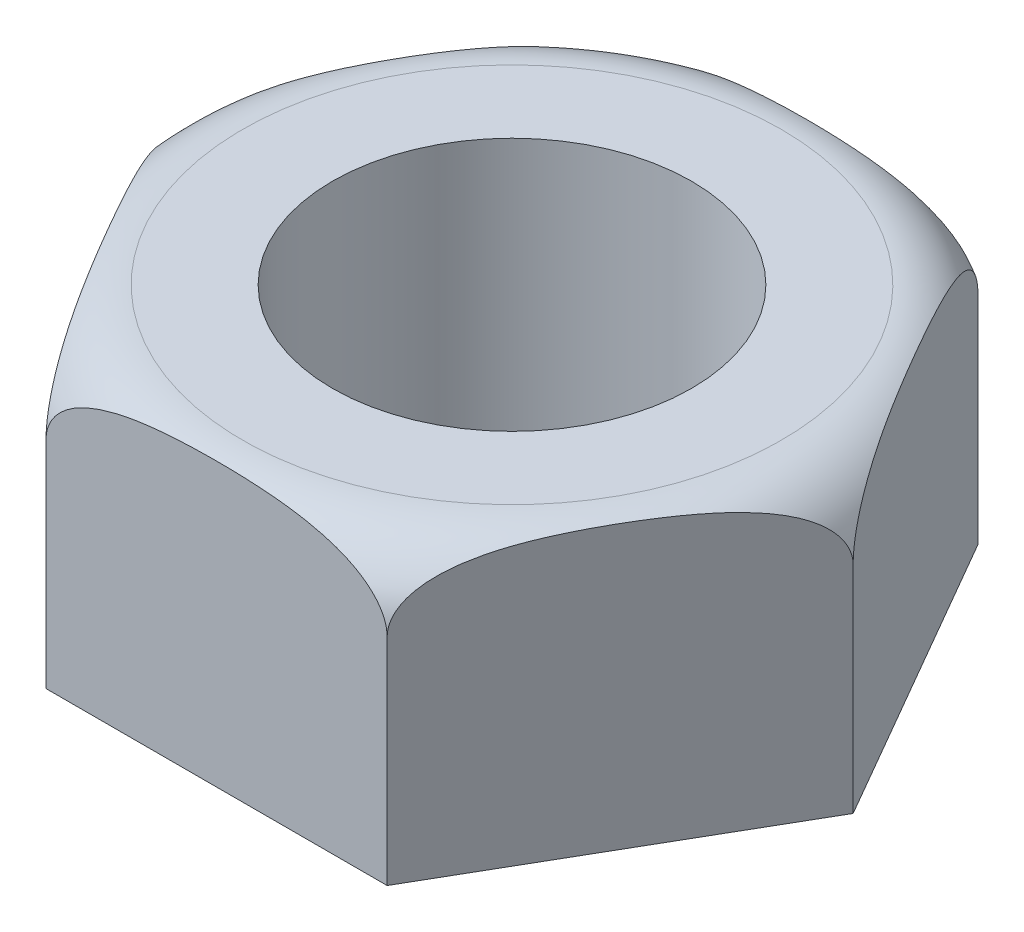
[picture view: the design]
ISO-10303-21;
HEADER;
FILE_DESCRIPTION(('STEP AP214'),'2;1');
FILE_NAME('part.step','',(''),(''),'','','');
FILE_SCHEMA(('AUTOMOTIVE_DESIGN { 1 0 10303 214 1 1 1 1 }'));
ENDSEC;
DATA;
#1=APPLICATION_CONTEXT('core data for automotive mechanical design processes');
#2=APPLICATION_PROTOCOL_DEFINITION('international standard','automotive_design',2000,#1);
#3=PRODUCT_CONTEXT('',#1,'mechanical');
#4=PRODUCT('Part','Part','',(#3));
#5=PRODUCT_RELATED_PRODUCT_CATEGORY('part','',(#4));
#6=PRODUCT_DEFINITION_FORMATION('','',#4);
#7=PRODUCT_DEFINITION_CONTEXT('part definition',#1,'design');
#8=PRODUCT_DEFINITION('design','',#6,#7);
#9=PRODUCT_DEFINITION_SHAPE('','',#8);
#10=(LENGTH_UNIT() NAMED_UNIT(*) SI_UNIT(.MILLI.,.METRE.));
#11=(NAMED_UNIT(*) PLANE_ANGLE_UNIT() SI_UNIT($,.RADIAN.));
#12=(NAMED_UNIT(*) SI_UNIT($,.STERADIAN.) SOLID_ANGLE_UNIT());
#13=UNCERTAINTY_MEASURE_WITH_UNIT(LENGTH_MEASURE(1.E-05),#10,'distance_accuracy_value','');
#14=(GEOMETRIC_REPRESENTATION_CONTEXT(3) GLOBAL_UNCERTAINTY_ASSIGNED_CONTEXT((#13)) GLOBAL_UNIT_ASSIGNED_CONTEXT((#10,
#11,#12)) REPRESENTATION_CONTEXT('',''));
#15=CARTESIAN_POINT('',(0.,0.,0.));
#16=DIRECTION('',(0.,0.,1.));
#17=DIRECTION('',(1.,0.,0.));
#18=AXIS2_PLACEMENT_3D('',#15,#16,#17);
#19=CARTESIAN_POINT('',(4.75,8.00000000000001,8.22724133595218));
#20=DIRECTION('',(0.,-1.,0.));
#21=DIRECTION('',(0.,0.,-1.));
#22=AXIS2_PLACEMENT_3D('',#19,#20,#21);
#23=PLANE('',#22);
#24=CARTESIAN_POINT('',(0.,8.00000000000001,0.));
#25=DIRECTION('',(0.,-1.,0.));
#26=DIRECTION('',(0.,0.,-1.));
#27=AXIS2_PLACEMENT_3D('',#24,#25,#26);
#28=CIRCLE('',#27,7.49999999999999);
#29=CARTESIAN_POINT('',(0.,8.00000000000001,-7.50000000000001));
#30=VERTEX_POINT('',#29);
#31=EDGE_CURVE('E214',#30,#30,#28,.T.);
#32=ORIENTED_EDGE('',*,*,#31,.F.);
#33=EDGE_LOOP('',(#32));
#34=FACE_BOUND('',#33,.T.);
#35=CARTESIAN_POINT('',(0.,8.00000000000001,0.));
#36=DIRECTION('',(0.,1.,0.));
#37=DIRECTION('',(0.,0.,1.));
#38=AXIS2_PLACEMENT_3D('',#35,#36,#37);
#39=CIRCLE('',#38,5.);
#40=CARTESIAN_POINT('',(0.,8.00000000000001,5.00000000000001));
#41=VERTEX_POINT('',#40);
#42=EDGE_CURVE('E134',#41,#41,#39,.T.);
#43=ORIENTED_EDGE('',*,*,#42,.F.);
#44=EDGE_LOOP('',(#43));
#45=FACE_BOUND('',#44,.T.);
#46=ADVANCED_FACE('F32',(#34,#45),#23,.F.);
#47=CARTESIAN_POINT('',(4.75,0.,8.22724133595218));
#48=DIRECTION('',(0.,-1.,0.));
#49=DIRECTION('',(0.,0.,-1.));
#50=AXIS2_PLACEMENT_3D('',#47,#48,#49);
#51=PLANE('',#50);
#52=DIRECTION('',(0.5,0.,-0.866025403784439));
#53=VECTOR('',#52,1.);
#54=CARTESIAN_POINT('',(4.75,0.,8.22724133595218));
#55=LINE('',#54,#53);
#56=CARTESIAN_POINT('',(4.75,0.,8.22724133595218));
#57=VERTEX_POINT('',#56);
#58=CARTESIAN_POINT('',(9.5,0.,0.));
#59=VERTEX_POINT('',#58);
#60=EDGE_CURVE('E132',#57,#59,#55,.T.);
#61=ORIENTED_EDGE('',*,*,#60,.F.);
#62=DIRECTION('',(1.,0.,0.));
#63=VECTOR('',#62,1.);
#64=CARTESIAN_POINT('',(-4.75000000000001,0.,8.22724133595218));
#65=LINE('',#64,#63);
#66=CARTESIAN_POINT('',(-4.75000000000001,0.,8.22724133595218));
#67=VERTEX_POINT('',#66);
#68=EDGE_CURVE('E121',#67,#57,#65,.T.);
#69=ORIENTED_EDGE('',*,*,#68,.F.);
#70=DIRECTION('',(0.500000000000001,0.,0.86602540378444));
#71=VECTOR('',#70,1.);
#72=CARTESIAN_POINT('',(-9.50000000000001,0.,0.));
#73=LINE('',#72,#71);
#74=CARTESIAN_POINT('',(-9.50000000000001,0.,0.));
#75=VERTEX_POINT('',#74);
#76=EDGE_CURVE('E123',#75,#67,#73,.T.);
#77=ORIENTED_EDGE('',*,*,#76,.F.);
#78=DIRECTION('',(-0.500000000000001,0.,0.86602540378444));
#79=VECTOR('',#78,1.);
#80=CARTESIAN_POINT('',(-4.75000000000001,0.,-8.22724133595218));
#81=LINE('',#80,#79);
#82=CARTESIAN_POINT('',(-4.75000000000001,0.,-8.22724133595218));
#83=VERTEX_POINT('',#82);
#84=EDGE_CURVE('E126',#83,#75,#81,.T.);
#85=ORIENTED_EDGE('',*,*,#84,.F.);
#86=DIRECTION('',(-1.,0.,0.));
#87=VECTOR('',#86,1.);
#88=CARTESIAN_POINT('',(4.74999999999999,0.,-8.22724133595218));
#89=LINE('',#88,#87);
#90=CARTESIAN_POINT('',(4.74999999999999,0.,-8.22724133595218));
#91=VERTEX_POINT('',#90);
#92=EDGE_CURVE('E129',#91,#83,#89,.T.);
#93=ORIENTED_EDGE('',*,*,#92,.F.);
#94=DIRECTION('',(-0.500000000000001,0.,-0.86602540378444));
#95=VECTOR('',#94,1.);
#96=CARTESIAN_POINT('',(9.5,0.,0.));
#97=LINE('',#96,#95);
#98=EDGE_CURVE('E111',#59,#91,#97,.T.);
#99=ORIENTED_EDGE('',*,*,#98,.F.);
#100=EDGE_LOOP('',(#61,#69,#77,#85,#93,#99));
#101=FACE_BOUND('',#100,.T.);
#102=CARTESIAN_POINT('',(0.,0.,0.));
#103=DIRECTION('',(0.,1.,0.));
#104=DIRECTION('',(0.,0.,1.));
#105=AXIS2_PLACEMENT_3D('',#102,#103,#104);
#106=CIRCLE('',#105,5.);
#107=CARTESIAN_POINT('',(0.,0.,5.00000000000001));
#108=VERTEX_POINT('',#107);
#109=EDGE_CURVE('E137',#108,#108,#106,.T.);
#110=ORIENTED_EDGE('',*,*,#109,.T.);
#111=EDGE_LOOP('',(#110));
#112=FACE_BOUND('',#111,.T.);
#113=ADVANCED_FACE('F185',(#101,#112),#51,.T.);
#114=CARTESIAN_POINT('',(4.75,8.00000000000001,8.22724133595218));
#115=DIRECTION('',(-0.866025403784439,0.,-0.5));
#116=DIRECTION('',(-0.5,0.,0.866025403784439));
#117=AXIS2_PLACEMENT_3D('',#114,#115,#116);
#118=PLANE('',#117);
#119=DIRECTION('',(0.,-1.,0.));
#120=VECTOR('',#119,1.);
#121=CARTESIAN_POINT('',(9.5,8.00000000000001,0.));
#122=LINE('',#121,#120);
#123=CARTESIAN_POINT('',(9.5,6.00000000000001,0.));
#124=VERTEX_POINT('',#123);
#125=EDGE_CURVE('E46',#124,#59,#122,.T.);
#126=ORIENTED_EDGE('',*,*,#125,.F.);
#127=CARTESIAN_POINT('',(9.49999999,5.9998,1.73205078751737E-08));
#128=CARTESIAN_POINT('',(9.50000570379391,6.02953854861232,-9.87926084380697E-06));
#129=CARTESIAN_POINT('',(9.49934209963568,6.05926118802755,0.00113951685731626));
#130=CARTESIAN_POINT('',(9.49670692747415,6.11845298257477,0.00570376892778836));
#131=CARTESIAN_POINT('',(9.4947362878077,6.14792230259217,0.009117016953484));
#132=CARTESIAN_POINT('',(9.48695380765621,6.23517168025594,0.0225966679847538));
#133=CARTESIAN_POINT('',(9.47927026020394,6.29231817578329,0.0359049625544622));
#134=CARTESIAN_POINT('',(9.45949602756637,6.40322520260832,0.0701549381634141));
#135=CARTESIAN_POINT('',(9.44741651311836,6.45699391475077,0.0910772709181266));
#136=CARTESIAN_POINT('',(9.41956311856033,6.56064404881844,0.139320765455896));
#137=CARTESIAN_POINT('',(9.40378132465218,6.61051683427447,0.166655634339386));
#138=CARTESIAN_POINT('',(9.35888397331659,6.73463561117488,0.244420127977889));
#139=CARTESIAN_POINT('',(9.32745343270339,6.80552710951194,0.298859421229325));
#140=CARTESIAN_POINT('',(9.25945945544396,6.93663016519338,0.416628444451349));
#141=CARTESIAN_POINT('',(9.22288378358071,6.99681546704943,0.479979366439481));
#142=CARTESIAN_POINT('',(9.15250995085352,7.09866418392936,0.601870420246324));
#143=CARTESIAN_POINT('',(9.11921583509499,7.14174925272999,0.659537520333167));
#144=CARTESIAN_POINT('',(9.05087560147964,7.22201196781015,0.777906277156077));
#145=CARTESIAN_POINT('',(9.0158281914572,7.25918517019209,0.83861017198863));
#146=CARTESIAN_POINT('',(8.94441863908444,7.32840115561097,0.962295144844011));
#147=CARTESIAN_POINT('',(8.90805407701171,7.36043384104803,1.02528041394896));
#148=CARTESIAN_POINT('',(8.83442786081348,7.41994367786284,1.15280476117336));
#149=CARTESIAN_POINT('',(8.79716649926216,7.44742229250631,1.21734333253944));
#150=CARTESIAN_POINT('',(8.70691244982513,7.50865232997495,1.37366793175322));
#151=CARTESIAN_POINT('',(8.65359886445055,7.54050535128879,1.46600977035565));
#152=CARTESIAN_POINT('',(8.54611149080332,7.59783939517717,1.65218336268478));
#153=CARTESIAN_POINT('',(8.49193727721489,7.62331715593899,1.74601585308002));
#154=CARTESIAN_POINT('',(8.38294500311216,7.6690358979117,1.93479600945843));
#155=CARTESIAN_POINT('',(8.32812595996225,7.68926737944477,2.02974537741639));
#156=CARTESIAN_POINT('',(8.21812420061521,7.72535220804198,2.22027401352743));
#157=CARTESIAN_POINT('',(8.1629414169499,7.74120471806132,2.31585339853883));
#158=CARTESIAN_POINT('',(8.05212864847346,7.76932967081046,2.50778674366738));
#159=CARTESIAN_POINT('',(7.99649775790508,7.78158760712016,2.60414227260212));
#160=CARTESIAN_POINT('',(7.88508651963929,7.80304965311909,2.79711219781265));
#161=CARTESIAN_POINT('',(7.82930615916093,7.81225349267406,2.89372661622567));
#162=CARTESIAN_POINT('',(7.71771510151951,7.82807918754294,3.08700799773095));
#163=CARTESIAN_POINT('',(7.66190449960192,7.83470377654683,3.18367479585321));
#164=CARTESIAN_POINT('',(7.55022830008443,7.84574609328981,3.3771036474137));
#165=CARTESIAN_POINT('',(7.49436270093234,7.85016375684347,3.4738657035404));
#166=CARTESIAN_POINT('',(7.36497862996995,7.85813362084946,3.69796548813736));
#167=CARTESIAN_POINT('',(7.29144917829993,7.86097352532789,3.82532223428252));
#168=CARTESIAN_POINT('',(7.14437827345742,7.86357402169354,4.08005651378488));
#169=CARTESIAN_POINT('',(7.07083682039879,7.86333464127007,4.20743404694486));
#170=CARTESIAN_POINT('',(6.92391404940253,7.85975368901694,4.4619117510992));
#171=CARTESIAN_POINT('',(6.85053269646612,7.85641810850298,4.5890119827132));
#172=CARTESIAN_POINT('',(6.70383188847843,7.84631582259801,4.84310523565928));
#173=CARTESIAN_POINT('',(6.63051242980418,7.8395493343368,4.97009826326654));
#174=CARTESIAN_POINT('',(6.48229282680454,7.82172370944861,5.2268221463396));
#175=CARTESIAN_POINT('',(6.40739547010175,7.81056863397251,5.35654817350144));
#176=CARTESIAN_POINT('',(6.25782508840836,7.78290463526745,5.61561167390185));
#177=CARTESIAN_POINT('',(6.18315211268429,7.76639461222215,5.74494906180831));
#178=CARTESIAN_POINT('',(6.03429411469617,7.72654851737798,6.00277867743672));
#179=CARTESIAN_POINT('',(5.96010883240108,7.70321644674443,6.13127135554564));
#180=CARTESIAN_POINT('',(5.81258009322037,7.64776448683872,6.38679862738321));
#181=CARTESIAN_POINT('',(5.73923620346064,7.61564934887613,6.51383397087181));
#182=CARTESIAN_POINT('',(5.59146025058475,7.53873440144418,6.76978942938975));
#183=CARTESIAN_POINT('',(5.51707923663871,7.49353181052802,6.89862112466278));
#184=CARTESIAN_POINT('',(5.37111873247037,7.38716305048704,7.15143213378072));
#185=CARTESIAN_POINT('',(5.29953820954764,7.32600283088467,7.27541323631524));
#186=CARTESIAN_POINT('',(5.17937365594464,7.20116047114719,7.48354434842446));
#187=CARTESIAN_POINT('',(5.1295960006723,7.14213802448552,7.56976177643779));
#188=CARTESIAN_POINT('',(5.03486652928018,7.01010975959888,7.7338380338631));
#189=CARTESIAN_POINT('',(4.98990435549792,6.9371349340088,7.81171480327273));
#190=CARTESIAN_POINT('',(4.92242614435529,6.8038929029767,7.92859049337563));
#191=CARTESIAN_POINT('',(4.897608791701,6.74831405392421,7.9715754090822));
#192=CARTESIAN_POINT('',(4.8524501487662,6.63023767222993,8.04979247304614));
#193=CARTESIAN_POINT('',(4.83210382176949,6.5677480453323,8.08503334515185));
#194=CARTESIAN_POINT('',(4.80038822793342,6.44799425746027,8.13996636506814));
#195=CARTESIAN_POINT('',(4.78806973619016,6.39174158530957,8.16130261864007));
#196=CARTESIAN_POINT('',(4.76830108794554,6.27594427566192,8.19554292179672));
#197=CARTESIAN_POINT('',(4.76084014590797,6.21640725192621,8.20846565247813));
#198=CARTESIAN_POINT('',(4.75407698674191,6.13023460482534,8.22017978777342));
#199=CARTESIAN_POINT('',(4.75254893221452,6.10424504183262,8.22282645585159));
#200=CARTESIAN_POINT('',(4.75050876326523,6.05210815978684,8.22636013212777));
#201=CARTESIAN_POINT('',(4.74999661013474,6.02596084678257,8.22724720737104));
#202=CARTESIAN_POINT('',(4.75000001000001,5.9998,8.22724131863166));
#203=B_SPLINE_CURVE_WITH_KNOTS('',3,(#127,#128,#129,#130,#131,#132,#133,#134,#135,#136,#137,
#138,#139,#140,#141,#142,#143,#144,#145,#146,#147,#148,#149,#150,#151,#152,#153,#154,#155,#156,
#157,#158,#159,#160,#161,#162,#163,#164,#165,#166,#167,#168,#169,#170,#171,#172,#173,#174,#175,
#176,#177,#178,#179,#180,#181,#182,#183,#184,#185,#186,#187,#188,#189,#190,#191,#192,#193,#194,
#195,#196,#197,#198,#199,#200,#201,#202),.UNSPECIFIED.,.F.,.F.,(4,2,2,2,2,2,2,2,2,2,2,2,2,2,2,2,
2,2,2,2,2,2,2,2,2,2,2,2,2,2,2,2,2,2,2,2,2,4),(0.,0.0891552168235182,0.178247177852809,
0.354877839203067,0.531062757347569,0.707627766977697,0.990252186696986,1.27356042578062,
1.51115713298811,1.74893160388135,1.9871675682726,2.22532683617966,2.55891555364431,
2.89267459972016,3.22703384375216,3.56145695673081,3.89721167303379,4.23299607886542,
4.56842361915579,4.90386091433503,5.34508340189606,5.78630192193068,6.22666843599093,
6.66700708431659,7.11756063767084,7.56820678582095,8.01858915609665,8.46872836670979,
8.93454308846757,9.40018438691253,9.74654054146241,10.0921360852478,10.3150195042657,
10.5376505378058,10.7211584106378,10.9042574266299,10.9826961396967,11.0611318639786),.UNSPECIFIED.);
#204=CARTESIAN_POINT('',(4.74999999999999,6.00000000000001,8.22724133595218));
#205=VERTEX_POINT('',#204);
#206=EDGE_CURVE('E95',#124,#205,#203,.T.);
#207=ORIENTED_EDGE('',*,*,#206,.T.);
#208=DIRECTION('',(0.,-1.,0.));
#209=VECTOR('',#208,1.);
#210=CARTESIAN_POINT('',(4.75,8.00000000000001,8.22724133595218));
#211=LINE('',#210,#209);
#212=EDGE_CURVE('E60',#205,#57,#211,.T.);
#213=ORIENTED_EDGE('',*,*,#212,.T.);
#214=ORIENTED_EDGE('',*,*,#60,.T.);
#215=EDGE_LOOP('',(#126,#207,#213,#214));
#216=FACE_BOUND('',#215,.T.);
#217=ADVANCED_FACE('F34',(#216),#118,.F.);
#218=CARTESIAN_POINT('',(9.5,8.00000000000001,0.));
#219=DIRECTION('',(-0.86602540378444,0.,0.500000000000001));
#220=DIRECTION('',(0.500000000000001,0.,0.86602540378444));
#221=AXIS2_PLACEMENT_3D('',#218,#219,#220);
#222=PLANE('',#221);
#223=DIRECTION('',(0.,-1.,0.));
#224=VECTOR('',#223,1.);
#225=CARTESIAN_POINT('',(4.74999999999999,8.00000000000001,-8.22724133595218));
#226=LINE('',#225,#224);
#227=CARTESIAN_POINT('',(4.74999999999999,6.00000000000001,-8.22724133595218));
#228=VERTEX_POINT('',#227);
#229=EDGE_CURVE('E104',#228,#91,#226,.T.);
#230=ORIENTED_EDGE('',*,*,#229,.F.);
#231=CARTESIAN_POINT('',(4.75000001,5.9998,-8.22724131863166));
#232=CARTESIAN_POINT('',(4.74999429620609,6.02953854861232,-8.22725121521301));
#233=CARTESIAN_POINT('',(4.75065790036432,6.05926118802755,-8.22610181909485));
#234=CARTESIAN_POINT('',(4.75329307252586,6.11845298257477,-8.22153756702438));
#235=CARTESIAN_POINT('',(4.7552637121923,6.14792230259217,-8.21812431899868));
#236=CARTESIAN_POINT('',(4.76304619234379,6.23517168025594,-8.20464466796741));
#237=CARTESIAN_POINT('',(4.77072973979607,6.29231817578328,-8.1913363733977));
#238=CARTESIAN_POINT('',(4.79050397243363,6.40322520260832,-8.15708639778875));
#239=CARTESIAN_POINT('',(4.80258348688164,6.45699391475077,-8.13616406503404));
#240=CARTESIAN_POINT('',(4.83043688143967,6.56064404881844,-8.08792057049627));
#241=CARTESIAN_POINT('',(4.84621867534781,6.61051683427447,-8.06058570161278));
#242=CARTESIAN_POINT('',(4.8911160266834,6.73463561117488,-7.98282120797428));
#243=CARTESIAN_POINT('',(4.92254656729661,6.80552710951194,-7.92838191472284));
#244=CARTESIAN_POINT('',(4.99054054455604,6.93663016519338,-7.81061289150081));
#245=CARTESIAN_POINT('',(5.0271162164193,6.99681546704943,-7.74726196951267));
#246=CARTESIAN_POINT('',(5.09749004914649,7.09866418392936,-7.62537091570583));
#247=CARTESIAN_POINT('',(5.13078416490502,7.14174925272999,-7.56770381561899));
#248=CARTESIAN_POINT('',(5.19912439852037,7.22201196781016,-7.44933505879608));
#249=CARTESIAN_POINT('',(5.2341718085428,7.2591851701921,-7.38863116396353));
#250=CARTESIAN_POINT('',(5.30558136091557,7.32840115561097,-7.26494619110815));
#251=CARTESIAN_POINT('',(5.34194592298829,7.36043384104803,-7.2019609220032));
#252=CARTESIAN_POINT('',(5.41557213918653,7.41994367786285,-7.0744365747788));
#253=CARTESIAN_POINT('',(5.45283350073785,7.44742229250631,-7.00989800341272));
#254=CARTESIAN_POINT('',(5.54308755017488,7.50865232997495,-6.85357340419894));
#255=CARTESIAN_POINT('',(5.59640113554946,7.5405053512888,-6.76123156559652));
#256=CARTESIAN_POINT('',(5.70388850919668,7.59783939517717,-6.57505797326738));
#257=CARTESIAN_POINT('',(5.75806272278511,7.62331715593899,-6.48122548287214));
#258=CARTESIAN_POINT('',(5.86705499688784,7.6690358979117,-6.29244532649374));
#259=CARTESIAN_POINT('',(5.92187404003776,7.68926737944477,-6.19749595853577));
#260=CARTESIAN_POINT('',(6.03187579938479,7.72535220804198,-6.00696732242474));
#261=CARTESIAN_POINT('',(6.0870585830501,7.74120471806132,-5.91138793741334));
#262=CARTESIAN_POINT('',(6.19787135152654,7.76932967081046,-5.71945459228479));
#263=CARTESIAN_POINT('',(6.25350224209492,7.78158760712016,-5.62309906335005));
#264=CARTESIAN_POINT('',(6.36491348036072,7.80304965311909,-5.43012913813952));
#265=CARTESIAN_POINT('',(6.42069384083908,7.81225349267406,-5.3335147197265));
#266=CARTESIAN_POINT('',(6.53228489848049,7.82807918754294,-5.14023333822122));
#267=CARTESIAN_POINT('',(6.58809550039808,7.83470377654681,-5.04356654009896));
#268=CARTESIAN_POINT('',(6.69977169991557,7.84574609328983,-4.85013768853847));
#269=CARTESIAN_POINT('',(6.75563729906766,7.85016375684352,-4.75337563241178));
#270=CARTESIAN_POINT('',(6.88502137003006,7.85813362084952,-4.52927584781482));
#271=CARTESIAN_POINT('',(6.95855082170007,7.86097352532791,-4.40191910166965));
#272=CARTESIAN_POINT('',(7.10562172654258,7.86357402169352,-4.14718482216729));
#273=CARTESIAN_POINT('',(7.17916317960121,7.86333464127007,-4.01980728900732));
#274=CARTESIAN_POINT('',(7.32608595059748,7.85975368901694,-3.76532958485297));
#275=CARTESIAN_POINT('',(7.39946730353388,7.85641810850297,-3.63822935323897));
#276=CARTESIAN_POINT('',(7.54616811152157,7.84631582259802,-3.38413610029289));
#277=CARTESIAN_POINT('',(7.61948757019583,7.83954933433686,-3.25714307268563));
#278=CARTESIAN_POINT('',(7.76770717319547,7.82172370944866,-3.00041918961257));
#279=CARTESIAN_POINT('',(7.84260452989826,7.81056863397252,-2.87069316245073));
#280=CARTESIAN_POINT('',(7.99217491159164,7.78290463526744,-2.61162966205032));
#281=CARTESIAN_POINT('',(8.06684788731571,7.76639461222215,-2.48229227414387));
#282=CARTESIAN_POINT('',(8.21570588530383,7.72654851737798,-2.22446265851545));
#283=CARTESIAN_POINT('',(8.28989116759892,7.70321644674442,-2.09596998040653));
#284=CARTESIAN_POINT('',(8.43741990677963,7.64776448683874,-1.84044270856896));
#285=CARTESIAN_POINT('',(8.51076379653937,7.61564934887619,-1.71340736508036));
#286=CARTESIAN_POINT('',(8.65853974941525,7.53873440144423,-1.45745190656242));
#287=CARTESIAN_POINT('',(8.73292076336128,7.49353181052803,-1.32862021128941));
#288=CARTESIAN_POINT('',(8.87888126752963,7.38716305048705,-1.07580920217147));
#289=CARTESIAN_POINT('',(8.95046179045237,7.32600283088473,-0.95182809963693));
#290=CARTESIAN_POINT('',(9.07062634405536,7.20116047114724,-0.743696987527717));
#291=CARTESIAN_POINT('',(9.12040399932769,7.14213802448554,-0.6574795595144));
#292=CARTESIAN_POINT('',(9.21513347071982,7.0101097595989,-0.493403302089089));
#293=CARTESIAN_POINT('',(9.2600956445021,6.93713493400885,-0.415526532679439));
#294=CARTESIAN_POINT('',(9.32757385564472,6.80389290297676,-0.298650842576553));
#295=CARTESIAN_POINT('',(9.352391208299,6.74831405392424,-0.255665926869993));
#296=CARTESIAN_POINT('',(9.3975498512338,6.63023767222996,-0.177448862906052));
#297=CARTESIAN_POINT('',(9.41789617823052,6.56774804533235,-0.142207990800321));
#298=CARTESIAN_POINT('',(9.44961177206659,6.44799425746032,-0.0872749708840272));
#299=CARTESIAN_POINT('',(9.46193026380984,6.39174158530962,-0.065938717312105));
#300=CARTESIAN_POINT('',(9.48169891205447,6.27594427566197,-0.0316984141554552));
#301=CARTESIAN_POINT('',(9.48915985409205,6.21640725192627,-0.0187756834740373));
#302=CARTESIAN_POINT('',(9.49592301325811,6.13023460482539,-0.00706154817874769));
#303=CARTESIAN_POINT('',(9.49745106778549,6.10424504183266,-0.00441488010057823));
#304=CARTESIAN_POINT('',(9.49949123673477,6.05210815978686,-0.000881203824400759));
#305=CARTESIAN_POINT('',(9.50000338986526,6.02596084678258,5.87141886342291E-06));
#306=CARTESIAN_POINT('',(9.49999999,5.9998,-1.73205130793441E-08));
#307=B_SPLINE_CURVE_WITH_KNOTS('',3,(#231,#232,#233,#234,#235,#236,#237,#238,#239,#240,#241,
#242,#243,#244,#245,#246,#247,#248,#249,#250,#251,#252,#253,#254,#255,#256,#257,#258,#259,#260,
#261,#262,#263,#264,#265,#266,#267,#268,#269,#270,#271,#272,#273,#274,#275,#276,#277,#278,#279,
#280,#281,#282,#283,#284,#285,#286,#287,#288,#289,#290,#291,#292,#293,#294,#295,#296,#297,#298,
#299,#300,#301,#302,#303,#304,#305,#306),.UNSPECIFIED.,.F.,.F.,(4,2,2,2,2,2,2,2,2,2,2,2,2,2,2,2,
2,2,2,2,2,2,2,2,2,2,2,2,2,2,2,2,2,2,2,2,2,4),(0.,0.0891552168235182,0.178247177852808,
0.354877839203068,0.531062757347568,0.707627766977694,0.990252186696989,1.27356042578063,
1.51115713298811,1.74893160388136,1.9871675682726,2.22532683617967,2.55891555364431,
2.89267459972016,3.22703384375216,3.56145695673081,3.89721167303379,4.23299607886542,
4.56842361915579,4.90386091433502,5.34508340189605,5.78630192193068,6.22666843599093,
6.66700708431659,7.11756063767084,7.56820678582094,8.01858915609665,8.46872836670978,
8.93454308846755,9.40018438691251,9.74654054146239,10.0921360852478,10.3150195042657,
10.5376505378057,10.7211584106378,10.9042574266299,10.9826961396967,11.0611318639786),.UNSPECIFIED.);
#308=EDGE_CURVE('E90',#228,#124,#307,.T.);
#309=ORIENTED_EDGE('',*,*,#308,.T.);
#310=ORIENTED_EDGE('',*,*,#125,.T.);
#311=ORIENTED_EDGE('',*,*,#98,.T.);
#312=EDGE_LOOP('',(#230,#309,#310,#311));
#313=FACE_BOUND('',#312,.T.);
#314=ADVANCED_FACE('F109',(#313),#222,.F.);
#315=CARTESIAN_POINT('',(4.74999999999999,8.00000000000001,-8.22724133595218));
#316=DIRECTION('',(0.,0.,1.));
#317=DIRECTION('',(1.,0.,0.));
#318=AXIS2_PLACEMENT_3D('',#315,#316,#317);
#319=PLANE('',#318);
#320=DIRECTION('',(0.,-1.,0.));
#321=VECTOR('',#320,1.);
#322=CARTESIAN_POINT('',(-4.75000000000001,8.00000000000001,-8.22724133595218));
#323=LINE('',#322,#321);
#324=CARTESIAN_POINT('',(-4.75000000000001,6.00000000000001,-8.22724133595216));
#325=VERTEX_POINT('',#324);
#326=EDGE_CURVE('E106',#325,#83,#323,.T.);
#327=ORIENTED_EDGE('',*,*,#326,.F.);
#328=CARTESIAN_POINT('',(0.,7.86309421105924,-8.22724133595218));
#329=CARTESIAN_POINT('',(0.206684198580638,7.86309782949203,-8.22724133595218));
#330=CARTESIAN_POINT('',(0.413370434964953,7.86010584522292,-8.22724133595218));
#331=CARTESIAN_POINT('',(0.826620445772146,7.84753258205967,-8.22724133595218));
#332=CARTESIAN_POINT('',(1.03318416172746,7.83794924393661,-8.22724133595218));
#333=CARTESIAN_POINT('',(1.4452627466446,7.81035098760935,-8.22724133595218));
#334=CARTESIAN_POINT('',(1.65077894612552,7.79235698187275,-8.22724133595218));
#335=CARTESIAN_POINT('',(2.06041206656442,7.74477379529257,-8.22724133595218));
#336=CARTESIAN_POINT('',(2.26452989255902,7.71519301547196,-8.22724133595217));
#337=CARTESIAN_POINT('',(2.61614106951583,7.64959758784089,-8.22724133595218));
#338=CARTESIAN_POINT('',(2.76431978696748,7.61735919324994,-8.22724133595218));
#339=CARTESIAN_POINT('',(3.05799231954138,7.5412593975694,-8.22724133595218));
#340=CARTESIAN_POINT('',(3.20348124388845,7.49737869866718,-8.22724133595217));
#341=CARTESIAN_POINT('',(3.4906425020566,7.39399754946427,-8.22724133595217));
#342=CARTESIAN_POINT('',(3.63226588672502,7.33435365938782,-8.22724133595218));
#343=CARTESIAN_POINT('',(3.83687465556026,7.22993735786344,-8.22724133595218));
#344=CARTESIAN_POINT('',(3.90369987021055,7.19269224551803,-8.22724133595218));
#345=CARTESIAN_POINT('',(4.03382325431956,7.11252196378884,-8.22724133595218));
#346=CARTESIAN_POINT('',(4.09712427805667,7.06960148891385,-8.22724133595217));
#347=CARTESIAN_POINT('',(4.22060565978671,6.97609139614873,-8.22724133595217));
#348=CARTESIAN_POINT('',(4.28065351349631,6.92532429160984,-8.22724133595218));
#349=CARTESIAN_POINT('',(4.39371594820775,6.81630884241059,-8.22724133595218));
#350=CARTESIAN_POINT('',(4.44672688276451,6.75805664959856,-8.22724133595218));
#351=CARTESIAN_POINT('',(4.54354715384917,6.63298440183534,-8.22724133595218));
#352=CARTESIAN_POINT('',(4.58722851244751,6.56606321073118,-8.22724133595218));
#353=CARTESIAN_POINT('',(4.66079442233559,6.42502707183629,-8.22724133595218));
#354=CARTESIAN_POINT('',(4.69071703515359,6.35093266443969,-8.22724133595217));
#355=CARTESIAN_POINT('',(4.72740557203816,6.21937063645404,-8.22724133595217));
#356=CARTESIAN_POINT('',(4.73830722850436,6.16304796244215,-8.22724133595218));
#357=CARTESIAN_POINT('',(4.75039980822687,6.04936642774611,-8.22724133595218));
#358=CARTESIAN_POINT('',(4.75159558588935,5.99200809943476,-8.22724133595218));
#359=CARTESIAN_POINT('',(4.74417597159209,5.87796699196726,-8.22724133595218));
#360=CARTESIAN_POINT('',(4.73556478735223,5.82128393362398,-8.22724133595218));
#361=CARTESIAN_POINT('',(4.70922228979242,5.71008948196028,-8.22724133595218));
#362=CARTESIAN_POINT('',(4.69148569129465,5.65557936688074,-8.22724133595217));
#363=CARTESIAN_POINT('',(4.64219534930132,5.53554430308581,-8.22724133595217));
#364=CARTESIAN_POINT('',(4.60820278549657,5.47102431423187,-8.22724133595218));
#365=CARTESIAN_POINT('',(4.53019257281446,5.34837346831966,-8.22724133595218));
#366=CARTESIAN_POINT('',(4.48615618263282,5.29025486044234,-8.22724133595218));
#367=CARTESIAN_POINT('',(4.36826739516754,5.15495744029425,-8.22724133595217));
#368=CARTESIAN_POINT('',(4.29009919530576,5.08156629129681,-8.22724133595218));
#369=CARTESIAN_POINT('',(4.12356437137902,4.94762790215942,-8.22724133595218));
#370=CARTESIAN_POINT('',(4.03517935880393,4.88710439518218,-8.22724133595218));
#371=CARTESIAN_POINT('',(3.8619969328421,4.78305623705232,-8.22724133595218));
#372=CARTESIAN_POINT('',(3.77786807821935,4.73839551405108,-8.22724133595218));
#373=CARTESIAN_POINT('',(3.60605635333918,4.65643568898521,-8.22724133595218));
#374=CARTESIAN_POINT('',(3.5183704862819,4.61914295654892,-8.22724133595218));
#375=CARTESIAN_POINT('',(3.3403799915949,4.5507381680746,-8.22724133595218));
#376=CARTESIAN_POINT('',(3.25006891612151,4.51964312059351,-8.22724133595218));
#377=CARTESIAN_POINT('',(3.06784548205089,4.46281002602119,-8.22724133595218));
#378=CARTESIAN_POINT('',(2.97593388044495,4.43706951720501,-8.22724133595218));
#379=CARTESIAN_POINT('',(2.73297019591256,4.3753681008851,-8.22724133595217));
#380=CARTESIAN_POINT('',(2.58097839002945,4.34312158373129,-8.22724133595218));
#381=CARTESIAN_POINT('',(2.27531090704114,4.28775252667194,-8.22724133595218));
#382=CARTESIAN_POINT('',(2.12163417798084,4.2646360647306,-8.22724133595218));
#383=CARTESIAN_POINT('',(1.81301597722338,4.22540230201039,-8.22724133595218));
#384=CARTESIAN_POINT('',(1.65807228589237,4.20930290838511,-8.22724133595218));
#385=CARTESIAN_POINT('',(1.347765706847,4.18261700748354,-8.22724133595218));
#386=CARTESIAN_POINT('',(1.1924029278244,4.17202918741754,-8.22724133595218));
#387=CARTESIAN_POINT('',(0.880551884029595,4.1552039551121,-8.22724133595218));
#388=CARTESIAN_POINT('',(0.724062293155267,4.14899196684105,-8.22724133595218));
#389=CARTESIAN_POINT('',(0.410973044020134,4.14031974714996,-8.22724133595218));
#390=CARTESIAN_POINT('',(0.254373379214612,4.13785976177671,-8.22724133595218));
#391=CARTESIAN_POINT('',(-0.0586204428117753,4.13640652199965,-8.22724133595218));
#392=CARTESIAN_POINT('',(-0.215014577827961,4.13740837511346,-8.22724133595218));
#393=CARTESIAN_POINT('',(-0.527730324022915,4.1429868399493,-8.22724133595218));
#394=CARTESIAN_POINT('',(-0.684051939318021,4.14756321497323,-8.22724133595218));
#395=CARTESIAN_POINT('',(-1.01826864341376,4.16172647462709,-8.22724133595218));
#396=CARTESIAN_POINT('',(-1.19613931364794,4.17192188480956,-8.22724133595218));
#397=CARTESIAN_POINT('',(-1.55144210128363,4.19904799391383,-8.22724133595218));
#398=CARTESIAN_POINT('',(-1.72887407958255,4.21598060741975,-8.22724133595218));
#399=CARTESIAN_POINT('',(-2.08147469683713,4.25864363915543,-8.22724133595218));
#400=CARTESIAN_POINT('',(-2.25665050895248,4.28431272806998,-8.22724133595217));
#401=CARTESIAN_POINT('',(-2.60494453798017,4.34752349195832,-8.22724133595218));
#402=CARTESIAN_POINT('',(-2.77806298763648,4.38506381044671,-8.22724133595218));
#403=CARTESIAN_POINT('',(-3.06972079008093,4.4628242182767,-8.22724133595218));
#404=CARTESIAN_POINT('',(-3.18932341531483,4.49900150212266,-8.22724133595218));
#405=CARTESIAN_POINT('',(-3.42499098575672,4.58131258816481,-8.22724133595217));
#406=CARTESIAN_POINT('',(-3.5410597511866,4.62743516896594,-8.22724133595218));
#407=CARTESIAN_POINT('',(-3.7687132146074,4.73258074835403,-8.22724133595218));
#408=CARTESIAN_POINT('',(-3.88024208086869,4.79172705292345,-8.22724133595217));
#409=CARTESIAN_POINT('',(-4.09352743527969,4.92559645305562,-8.22724133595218));
#410=CARTESIAN_POINT('',(-4.19531194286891,5.00027280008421,-8.22724133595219));
#411=CARTESIAN_POINT('',(-4.34424622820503,5.13395648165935,-8.22724133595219));
#412=CARTESIAN_POINT('',(-4.39676160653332,5.18695469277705,-8.22724133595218));
#413=CARTESIAN_POINT('',(-4.49386382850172,5.29991260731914,-8.22724133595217));
#414=CARTESIAN_POINT('',(-4.53844996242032,5.35987293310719,-8.22724133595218));
#415=CARTESIAN_POINT('',(-4.6174289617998,5.48738312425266,-8.22724133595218));
#416=CARTESIAN_POINT('',(-4.65168292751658,5.55502090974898,-8.22724133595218));
#417=CARTESIAN_POINT('',(-4.70594056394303,5.69579105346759,-8.22724133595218));
#418=CARTESIAN_POINT('',(-4.7259740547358,5.76891155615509,-8.22724133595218));
#419=CARTESIAN_POINT('',(-4.74770863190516,5.90689178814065,-8.22724133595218));
#420=CARTESIAN_POINT('',(-4.75166049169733,5.97139761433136,-8.22724133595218));
#421=CARTESIAN_POINT('',(-4.74706633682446,6.09996082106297,-8.22724133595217));
#422=CARTESIAN_POINT('',(-4.73852202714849,6.16401826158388,-8.22724133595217));
#423=CARTESIAN_POINT('',(-4.71150906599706,6.28197730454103,-8.22724133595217));
#424=CARTESIAN_POINT('',(-4.69433239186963,6.33618455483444,-8.22724133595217));
#425=CARTESIAN_POINT('',(-4.65211479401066,6.44140800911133,-8.22724133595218));
#426=CARTESIAN_POINT('',(-4.62707206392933,6.49242347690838,-8.22724133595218));
#427=CARTESIAN_POINT('',(-4.55726563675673,6.61350833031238,-8.22724133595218));
#428=CARTESIAN_POINT('',(-4.50874614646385,6.68141021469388,-8.22724133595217));
#429=CARTESIAN_POINT('',(-4.40153522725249,6.80863302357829,-8.22724133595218));
#430=CARTESIAN_POINT('',(-4.34281937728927,6.86793270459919,-8.22724133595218));
#431=CARTESIAN_POINT('',(-4.18223991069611,7.01038551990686,-8.22724133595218));
#432=CARTESIAN_POINT('',(-4.07506123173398,7.08749984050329,-8.22724133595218));
#433=CARTESIAN_POINT('',(-3.85058975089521,7.22500735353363,-8.22724133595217));
#434=CARTESIAN_POINT('',(-3.73327357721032,7.2853604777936,-8.22724133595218));
#435=CARTESIAN_POINT('',(-3.49483121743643,7.39172183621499,-8.22724133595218));
#436=CARTESIAN_POINT('',(-3.37380422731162,7.43795731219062,-8.22724133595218));
#437=CARTESIAN_POINT('',(-3.12824195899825,7.52010489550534,-8.22724133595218));
#438=CARTESIAN_POINT('',(-3.00370313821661,7.55600613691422,-8.22724133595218));
#439=CARTESIAN_POINT('',(-2.75236111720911,7.61957387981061,-8.22724133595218));
#440=CARTESIAN_POINT('',(-2.62555444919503,7.64722637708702,-8.22724133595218));
#441=CARTESIAN_POINT('',(-2.3706594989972,7.69587702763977,-8.22724133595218));
#442=CARTESIAN_POINT('',(-2.24257083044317,7.71687310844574,-8.22724133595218));
#443=CARTESIAN_POINT('',(-1.93925651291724,7.76014569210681,-8.22724133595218));
#444=CARTESIAN_POINT('',(-1.76371117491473,7.78014693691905,-8.22724133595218));
#445=CARTESIAN_POINT('',(-1.41192678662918,7.81276338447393,-8.22724133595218));
#446=CARTESIAN_POINT('',(-1.23568756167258,7.82537658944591,-8.22724133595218));
#447=CARTESIAN_POINT('',(-0.88291833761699,7.84489642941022,-8.22724133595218));
#448=CARTESIAN_POINT('',(-0.706388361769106,7.85180350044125,-8.22724133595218));
#449=CARTESIAN_POINT('',(-0.353239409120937,7.86090050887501,-8.22724133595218));
#450=CARTESIAN_POINT('',(-0.176620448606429,7.86309111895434,-8.22724133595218));
#451=CARTESIAN_POINT('',(0.,7.86309421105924,-8.22724133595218));
#452=B_SPLINE_CURVE_WITH_KNOTS('',3,(#328,#329,#330,#331,#332,#333,#334,#335,#336,#337,#338,
#339,#340,#341,#342,#343,#344,#345,#346,#347,#348,#349,#350,#351,#352,#353,#354,#355,#356,#357,
#358,#359,#360,#361,#362,#363,#364,#365,#366,#367,#368,#369,#370,#371,#372,#373,#374,#375,#376,
#377,#378,#379,#380,#381,#382,#383,#384,#385,#386,#387,#388,#389,#390,#391,#392,#393,#394,#395,
#396,#397,#398,#399,#400,#401,#402,#403,#404,#405,#406,#407,#408,#409,#410,#411,#412,#413,#414,
#415,#416,#417,#418,#419,#420,#421,#422,#423,#424,#425,#426,#427,#428,#429,#430,#431,#432,#433,
#434,#435,#436,#437,#438,#439,#440,#441,#442,#443,#444,#445,#446,#447,#448,#449,#450,#451),
.UNSPECIFIED.,.T.,.F.,(4,2,2,2,2,2,2,2,2,2,2,2,2,2,2,2,2,2,2,2,2,2,2,2,2,2,2,2,2,2,2,2,2,2,2,2,
2,2,2,2,2,2,2,2,2,2,2,2,2,2,2,2,2,2,2,2,2,2,2,2,2,4),(0.,0.62003251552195,1.24025882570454,
1.8589511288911,2.47719567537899,2.9317741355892,3.38711084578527,3.84674284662,
4.07602516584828,4.30511900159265,4.54047171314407,4.77594590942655,5.01446787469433,
5.25232597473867,5.42366572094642,5.59491976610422,5.76610036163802,5.93738021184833,
6.15495372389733,6.37293658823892,6.69280248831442,7.01325332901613,7.29858144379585,
7.5841551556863,7.87050210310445,8.15671711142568,8.62243096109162,9.08845432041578,
9.55566007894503,10.022754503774,10.4925408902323,10.9623580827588,11.4315115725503,
11.9006339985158,12.4350252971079,12.9695685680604,13.5004342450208,14.0312392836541,
14.4057708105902,14.7798819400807,15.1577002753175,15.5343973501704,15.7576422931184,
15.980907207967,16.2070519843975,16.4327211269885,16.6254194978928,16.8180915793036,
16.9879971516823,17.1579417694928,17.4068911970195,17.6564453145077,18.050325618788,
18.4451395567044,18.8332152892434,19.2216975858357,19.610835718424,20.0000948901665,
20.5299119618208,21.0598722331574,21.5897920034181,22.1196361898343),.UNSPECIFIED.);
#453=EDGE_CURVE('E93',#325,#228,#452,.T.);
#454=ORIENTED_EDGE('',*,*,#453,.T.);
#455=ORIENTED_EDGE('',*,*,#229,.T.);
#456=ORIENTED_EDGE('',*,*,#92,.T.);
#457=EDGE_LOOP('',(#327,#454,#455,#456));
#458=FACE_BOUND('',#457,.T.);
#459=ADVANCED_FACE('F102',(#458),#319,.F.);
#460=CARTESIAN_POINT('',(-4.75000000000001,8.00000000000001,-8.22724133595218));
#461=DIRECTION('',(0.86602540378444,0.,0.500000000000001));
#462=DIRECTION('',(0.500000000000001,0.,-0.86602540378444));
#463=AXIS2_PLACEMENT_3D('',#460,#461,#462);
#464=PLANE('',#463);
#465=DIRECTION('',(0.,-1.,0.));
#466=VECTOR('',#465,1.);
#467=CARTESIAN_POINT('',(-9.50000000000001,8.00000000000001,0.));
#468=LINE('',#467,#466);
#469=CARTESIAN_POINT('',(-9.5,6.00000000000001,0.));
#470=VERTEX_POINT('',#469);
#471=EDGE_CURVE('E114',#470,#75,#468,.T.);
#472=ORIENTED_EDGE('',*,*,#471,.F.);
#473=CARTESIAN_POINT('',(-9.49999999,5.9998,-1.73205260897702E-08));
#474=CARTESIAN_POINT('',(-9.50000570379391,6.02953854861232,9.87926082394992E-06));
#475=CARTESIAN_POINT('',(-9.49934209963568,6.05926118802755,-0.00113951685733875));
#476=CARTESIAN_POINT('',(-9.49670692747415,6.11845298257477,-0.00570376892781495));
#477=CARTESIAN_POINT('',(-9.4947362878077,6.14792230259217,-0.00911701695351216));
#478=CARTESIAN_POINT('',(-9.48695380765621,6.23517168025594,-0.0225966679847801));
#479=CARTESIAN_POINT('',(-9.47927026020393,6.29231817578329,-0.0359049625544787));
#480=CARTESIAN_POINT('',(-9.45949602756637,6.40322520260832,-0.0701549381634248));
#481=CARTESIAN_POINT('',(-9.44741651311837,6.45699391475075,-0.0910772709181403));
#482=CARTESIAN_POINT('',(-9.41956311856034,6.5606440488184,-0.139320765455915));
#483=CARTESIAN_POINT('',(-9.40378132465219,6.61051683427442,-0.166655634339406));
#484=CARTESIAN_POINT('',(-9.3588839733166,6.73463561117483,-0.244420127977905));
#485=CARTESIAN_POINT('',(-9.32745343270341,6.80552710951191,-0.298859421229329));
#486=CARTESIAN_POINT('',(-9.25945945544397,6.93663016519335,-0.416628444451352));
#487=CARTESIAN_POINT('',(-9.22288378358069,6.99681546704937,-0.479979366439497));
#488=CARTESIAN_POINT('',(-9.1525099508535,7.09866418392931,-0.601870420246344));
#489=CARTESIAN_POINT('',(-9.11921583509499,7.14174925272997,-0.65953752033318));
#490=CARTESIAN_POINT('',(-9.05087560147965,7.22201196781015,-0.777906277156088));
#491=CARTESIAN_POINT('',(-9.01582819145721,7.25918517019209,-0.838610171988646));
#492=CARTESIAN_POINT('',(-8.94441863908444,7.32840115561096,-0.962295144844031));
#493=CARTESIAN_POINT('',(-8.90805407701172,7.36043384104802,-1.02528041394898));
#494=CARTESIAN_POINT('',(-8.83442786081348,7.41994367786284,-1.15280476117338));
#495=CARTESIAN_POINT('',(-8.79716649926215,7.4474222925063,-1.21734333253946));
#496=CARTESIAN_POINT('',(-8.70691244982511,7.50865232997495,-1.37366793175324));
#497=CARTESIAN_POINT('',(-8.65359886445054,7.54050535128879,-1.46600977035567));
#498=CARTESIAN_POINT('',(-8.54611149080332,7.59783939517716,-1.65218336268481));
#499=CARTESIAN_POINT('',(-8.49193727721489,7.62331715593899,-1.74601585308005));
#500=CARTESIAN_POINT('',(-8.38294500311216,7.66903589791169,-1.93479600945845));
#501=CARTESIAN_POINT('',(-8.32812595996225,7.68926737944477,-2.02974537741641));
#502=CARTESIAN_POINT('',(-8.21812420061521,7.72535220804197,-2.22027401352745));
#503=CARTESIAN_POINT('',(-8.1629414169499,7.74120471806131,-2.31585339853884));
#504=CARTESIAN_POINT('',(-8.05212864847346,7.76932967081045,-2.5077867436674));
#505=CARTESIAN_POINT('',(-7.99649775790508,7.78158760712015,-2.60414227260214));
#506=CARTESIAN_POINT('',(-7.88508651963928,7.80304965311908,-2.79711219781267));
#507=CARTESIAN_POINT('',(-7.82930615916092,7.81225349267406,-2.89372661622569));
#508=CARTESIAN_POINT('',(-7.71771510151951,7.82807918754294,-3.08700799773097));
#509=CARTESIAN_POINT('',(-7.66190449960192,7.83470377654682,-3.18367479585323));
#510=CARTESIAN_POINT('',(-7.55022830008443,7.84574609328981,-3.37710364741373));
#511=CARTESIAN_POINT('',(-7.49436270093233,7.85016375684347,-3.47386570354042));
#512=CARTESIAN_POINT('',(-7.36497862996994,7.85813362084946,-3.69796548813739));
#513=CARTESIAN_POINT('',(-7.29144917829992,7.86097352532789,-3.82532223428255));
#514=CARTESIAN_POINT('',(-7.14437827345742,7.86357402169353,-4.0800565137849));
#515=CARTESIAN_POINT('',(-7.07083682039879,7.86333464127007,-4.20743404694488));
#516=CARTESIAN_POINT('',(-6.92391404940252,7.85975368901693,-4.46191175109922));
#517=CARTESIAN_POINT('',(-6.85053269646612,7.85641810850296,-4.58901198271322));
#518=CARTESIAN_POINT('',(-6.70383188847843,7.84631582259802,-4.8431052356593));
#519=CARTESIAN_POINT('',(-6.63051242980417,7.83954933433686,-4.97009826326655));
#520=CARTESIAN_POINT('',(-6.48229282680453,7.82172370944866,-5.22682214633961));
#521=CARTESIAN_POINT('',(-6.40739547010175,7.81056863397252,-5.35654817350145));
#522=CARTESIAN_POINT('',(-6.25782508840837,7.78290463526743,-5.61561167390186));
#523=CARTESIAN_POINT('',(-6.1831521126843,7.76639461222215,-5.74494906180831));
#524=CARTESIAN_POINT('',(-6.03429411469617,7.72654851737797,-6.00277867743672));
#525=CARTESIAN_POINT('',(-5.96010883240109,7.70321644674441,-6.13127135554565));
#526=CARTESIAN_POINT('',(-5.81258009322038,7.64776448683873,-6.38679862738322));
#527=CARTESIAN_POINT('',(-5.73923620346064,7.61564934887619,-6.51383397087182));
#528=CARTESIAN_POINT('',(-5.59146025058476,7.53873440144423,-6.76978942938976));
#529=CARTESIAN_POINT('',(-5.51707923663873,7.49353181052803,-6.89862112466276));
#530=CARTESIAN_POINT('',(-5.37111873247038,7.38716305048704,-7.1514321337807));
#531=CARTESIAN_POINT('',(-5.29953820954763,7.32600283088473,-7.27541323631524));
#532=CARTESIAN_POINT('',(-5.17937365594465,7.20116047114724,-7.48354434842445));
#533=CARTESIAN_POINT('',(-5.12959600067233,7.14213802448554,-7.56976177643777));
#534=CARTESIAN_POINT('',(-5.0348665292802,7.0101097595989,-7.73383803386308));
#535=CARTESIAN_POINT('',(-4.98990435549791,6.93713493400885,-7.81171480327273));
#536=CARTESIAN_POINT('',(-4.92242614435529,6.80389290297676,-7.92859049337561));
#537=CARTESIAN_POINT('',(-4.89760879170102,6.74831405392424,-7.97157540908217));
#538=CARTESIAN_POINT('',(-4.85245014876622,6.63023767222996,-8.04979247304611));
#539=CARTESIAN_POINT('',(-4.8321038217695,6.56774804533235,-8.08503334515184));
#540=CARTESIAN_POINT('',(-4.80038822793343,6.44799425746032,-8.13996636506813));
#541=CARTESIAN_POINT('',(-4.78806973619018,6.39174158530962,-8.16130261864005));
#542=CARTESIAN_POINT('',(-4.76830108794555,6.27594427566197,-8.1955429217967));
#543=CARTESIAN_POINT('',(-4.76084014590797,6.21640725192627,-8.20846565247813));
#544=CARTESIAN_POINT('',(-4.75407698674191,6.13023460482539,-8.22017978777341));
#545=CARTESIAN_POINT('',(-4.75254893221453,6.10424504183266,-8.22282645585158));
#546=CARTESIAN_POINT('',(-4.75050876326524,6.05210815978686,-8.22636013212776));
#547=CARTESIAN_POINT('',(-4.74999661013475,6.02596084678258,-8.22724720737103));
#548=CARTESIAN_POINT('',(-4.75000001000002,5.9998,-8.22724131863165));
#549=B_SPLINE_CURVE_WITH_KNOTS('',3,(#473,#474,#475,#476,#477,#478,#479,#480,#481,#482,#483,
#484,#485,#486,#487,#488,#489,#490,#491,#492,#493,#494,#495,#496,#497,#498,#499,#500,#501,#502,
#503,#504,#505,#506,#507,#508,#509,#510,#511,#512,#513,#514,#515,#516,#517,#518,#519,#520,#521,
#522,#523,#524,#525,#526,#527,#528,#529,#530,#531,#532,#533,#534,#535,#536,#537,#538,#539,#540,
#541,#542,#543,#544,#545,#546,#547,#548),.UNSPECIFIED.,.F.,.F.,(4,2,2,2,2,2,2,2,2,2,2,2,2,2,2,2,
2,2,2,2,2,2,2,2,2,2,2,2,2,2,2,2,2,2,2,2,2,4),(0.,0.0891552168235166,0.178247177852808,
0.354877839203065,0.531062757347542,0.707627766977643,0.99025218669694,1.27356042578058,
1.51115713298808,1.74893160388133,1.98716756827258,2.22532683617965,2.5589155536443,
2.89267459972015,3.22703384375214,3.56145695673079,3.89721167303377,4.23299607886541,
4.56842361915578,4.90386091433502,5.34508340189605,5.78630192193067,6.22666843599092,
6.66700708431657,7.11756063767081,7.56820678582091,8.01858915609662,8.46872836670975,
8.93454308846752,9.40018438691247,9.74654054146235,10.0921360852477,10.3150195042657,
10.5376505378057,10.7211584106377,10.9042574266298,10.9826961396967,11.0611318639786),.UNSPECIFIED.);
#550=EDGE_CURVE('E107',#470,#325,#549,.T.);
#551=ORIENTED_EDGE('',*,*,#550,.T.);
#552=ORIENTED_EDGE('',*,*,#326,.T.);
#553=ORIENTED_EDGE('',*,*,#84,.T.);
#554=EDGE_LOOP('',(#472,#551,#552,#553));
#555=FACE_BOUND('',#554,.T.);
#556=ADVANCED_FACE('F178',(#555),#464,.F.);
#557=CARTESIAN_POINT('',(-9.50000000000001,8.00000000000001,0.));
#558=DIRECTION('',(0.86602540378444,0.,-0.500000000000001));
#559=DIRECTION('',(-0.500000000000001,0.,-0.86602540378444));
#560=AXIS2_PLACEMENT_3D('',#557,#558,#559);
#561=PLANE('',#560);
#562=DIRECTION('',(0.,-1.,0.));
#563=VECTOR('',#562,1.);
#564=CARTESIAN_POINT('',(-4.75000000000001,8.00000000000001,8.22724133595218));
#565=LINE('',#564,#563);
#566=CARTESIAN_POINT('',(-4.75000000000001,6.00000000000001,8.22724133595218));
#567=VERTEX_POINT('',#566);
#568=EDGE_CURVE('E118',#567,#67,#565,.T.);
#569=ORIENTED_EDGE('',*,*,#568,.F.);
#570=CARTESIAN_POINT('',(-4.75000001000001,5.9998,8.22724131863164));
#571=CARTESIAN_POINT('',(-4.74999429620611,6.02953854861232,8.227251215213));
#572=CARTESIAN_POINT('',(-4.75065790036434,6.05926118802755,8.22610181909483));
#573=CARTESIAN_POINT('',(-4.75329307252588,6.11845298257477,8.22153756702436));
#574=CARTESIAN_POINT('',(-4.75526371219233,6.14792230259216,8.21812431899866));
#575=CARTESIAN_POINT('',(-4.76304619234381,6.23517168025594,8.2046446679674));
#576=CARTESIAN_POINT('',(-4.77072973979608,6.29231817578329,8.1913363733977));
#577=CARTESIAN_POINT('',(-4.79050397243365,6.40322520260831,8.15708639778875));
#578=CARTESIAN_POINT('',(-4.80258348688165,6.45699391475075,8.13616406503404));
#579=CARTESIAN_POINT('',(-4.83043688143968,6.5606440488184,8.08792057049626));
#580=CARTESIAN_POINT('',(-4.84621867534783,6.61051683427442,8.06058570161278));
#581=CARTESIAN_POINT('',(-4.89111602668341,6.73463561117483,7.98282120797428));
#582=CARTESIAN_POINT('',(-4.92254656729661,6.8055271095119,7.92838191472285));
#583=CARTESIAN_POINT('',(-4.99054054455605,6.93663016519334,7.81061289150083));
#584=CARTESIAN_POINT('',(-5.02711621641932,6.99681546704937,7.74726196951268));
#585=CARTESIAN_POINT('',(-5.09749004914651,7.09866418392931,7.62537091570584));
#586=CARTESIAN_POINT('',(-5.13078416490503,7.14174925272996,7.567703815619));
#587=CARTESIAN_POINT('',(-5.19912439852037,7.22201196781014,7.44933505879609));
#588=CARTESIAN_POINT('',(-5.23417180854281,7.25918517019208,7.38863116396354));
#589=CARTESIAN_POINT('',(-5.30558136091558,7.32840115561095,7.26494619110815));
#590=CARTESIAN_POINT('',(-5.3419459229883,7.36043384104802,7.2019609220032));
#591=CARTESIAN_POINT('',(-5.41557213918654,7.41994367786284,7.0744365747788));
#592=CARTESIAN_POINT('',(-5.45283350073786,7.4474222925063,7.00989800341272));
#593=CARTESIAN_POINT('',(-5.5430875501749,7.50865232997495,6.85357340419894));
#594=CARTESIAN_POINT('',(-5.59640113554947,7.54050535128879,6.76123156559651));
#595=CARTESIAN_POINT('',(-5.7038885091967,7.59783939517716,6.57505797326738));
#596=CARTESIAN_POINT('',(-5.75806272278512,7.62331715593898,6.48122548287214));
#597=CARTESIAN_POINT('',(-5.86705499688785,7.66903589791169,6.29244532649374));
#598=CARTESIAN_POINT('',(-5.92187404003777,7.68926737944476,6.19749595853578));
#599=CARTESIAN_POINT('',(-6.0318757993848,7.72535220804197,6.00696732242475));
#600=CARTESIAN_POINT('',(-6.08705858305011,7.74120471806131,5.91138793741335));
#601=CARTESIAN_POINT('',(-6.19787135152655,7.76932967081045,5.71945459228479));
#602=CARTESIAN_POINT('',(-6.25350224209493,7.78158760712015,5.62309906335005));
#603=CARTESIAN_POINT('',(-6.36491348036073,7.80304965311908,5.43012913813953));
#604=CARTESIAN_POINT('',(-6.42069384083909,7.81225349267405,5.3335147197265));
#605=CARTESIAN_POINT('',(-6.5322848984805,7.82807918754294,5.14023333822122));
#606=CARTESIAN_POINT('',(-6.58809550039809,7.83470377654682,5.04356654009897));
#607=CARTESIAN_POINT('',(-6.69977169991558,7.84574609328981,4.85013768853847));
#608=CARTESIAN_POINT('',(-6.75563729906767,7.85016375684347,4.75337563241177));
#609=CARTESIAN_POINT('',(-6.88502137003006,7.85813362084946,4.52927584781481));
#610=CARTESIAN_POINT('',(-6.95855082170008,7.86097352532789,4.40191910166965));
#611=CARTESIAN_POINT('',(-7.1056217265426,7.86357402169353,4.1471848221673));
#612=CARTESIAN_POINT('',(-7.17916317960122,7.86333464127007,4.01980728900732));
#613=CARTESIAN_POINT('',(-7.32608595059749,7.85975368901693,3.76532958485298));
#614=CARTESIAN_POINT('',(-7.39946730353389,7.85641810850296,3.63822935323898));
#615=CARTESIAN_POINT('',(-7.54616811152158,7.84631582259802,3.3841361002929));
#616=CARTESIAN_POINT('',(-7.61948757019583,7.83954933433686,3.25714307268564));
#617=CARTESIAN_POINT('',(-7.76770717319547,7.82172370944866,3.00041918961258));
#618=CARTESIAN_POINT('',(-7.84260452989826,7.81056863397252,2.87069316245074));
#619=CARTESIAN_POINT('',(-7.99217491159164,7.78290463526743,2.61162966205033));
#620=CARTESIAN_POINT('',(-8.06684788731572,7.76639461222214,2.48229227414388));
#621=CARTESIAN_POINT('',(-8.21570588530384,7.72654851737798,2.22446265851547));
#622=CARTESIAN_POINT('',(-8.28989116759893,7.70321644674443,2.09596998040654));
#623=CARTESIAN_POINT('',(-8.43741990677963,7.64776448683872,1.84044270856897));
#624=CARTESIAN_POINT('',(-8.51076379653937,7.61564934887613,1.71340736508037));
#625=CARTESIAN_POINT('',(-8.65853974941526,7.53873440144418,1.45745190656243));
#626=CARTESIAN_POINT('',(-8.7329207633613,7.49353181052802,1.32862021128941));
#627=CARTESIAN_POINT('',(-8.87888126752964,7.38716305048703,1.07580920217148));
#628=CARTESIAN_POINT('',(-8.95046179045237,7.32600283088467,0.951828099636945));
#629=CARTESIAN_POINT('',(-9.07062634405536,7.20116047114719,0.743696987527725));
#630=CARTESIAN_POINT('',(-9.1204039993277,7.14213802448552,0.657479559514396));
#631=CARTESIAN_POINT('',(-9.21513347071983,7.01010975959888,0.49340330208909));
#632=CARTESIAN_POINT('',(-9.26009564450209,6.9371349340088,0.415526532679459));
#633=CARTESIAN_POINT('',(-9.32757385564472,6.8038929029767,0.298650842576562));
#634=CARTESIAN_POINT('',(-9.35239120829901,6.74831405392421,0.255665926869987));
#635=CARTESIAN_POINT('',(-9.39754985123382,6.63023767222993,0.177448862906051));
#636=CARTESIAN_POINT('',(-9.41789617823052,6.5677480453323,0.14220799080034));
#637=CARTESIAN_POINT('',(-9.44961177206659,6.44799425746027,0.0872749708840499));
#638=CARTESIAN_POINT('',(-9.46193026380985,6.39174158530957,0.0659387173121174));
#639=CARTESIAN_POINT('',(-9.48169891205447,6.27594427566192,0.0316984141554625));
#640=CARTESIAN_POINT('',(-9.48915985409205,6.21640725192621,0.0187756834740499));
#641=CARTESIAN_POINT('',(-9.49592301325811,6.13023460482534,0.00706154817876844));
#642=CARTESIAN_POINT('',(-9.49745106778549,6.10424504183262,0.00441488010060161));
#643=CARTESIAN_POINT('',(-9.49949123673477,6.05210815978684,0.000881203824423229));
#644=CARTESIAN_POINT('',(-9.50000338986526,6.02596084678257,-5.87141884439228E-06));
#645=CARTESIAN_POINT('',(-9.49999999,5.9998,1.7320523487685E-08));
#646=B_SPLINE_CURVE_WITH_KNOTS('',3,(#570,#571,#572,#573,#574,#575,#576,#577,#578,#579,#580,
#581,#582,#583,#584,#585,#586,#587,#588,#589,#590,#591,#592,#593,#594,#595,#596,#597,#598,#599,
#600,#601,#602,#603,#604,#605,#606,#607,#608,#609,#610,#611,#612,#613,#614,#615,#616,#617,#618,
#619,#620,#621,#622,#623,#624,#625,#626,#627,#628,#629,#630,#631,#632,#633,#634,#635,#636,#637,
#638,#639,#640,#641,#642,#643,#644,#645),.UNSPECIFIED.,.F.,.F.,(4,2,2,2,2,2,2,2,2,2,2,2,2,2,2,2,
2,2,2,2,2,2,2,2,2,2,2,2,2,2,2,2,2,2,2,2,2,4),(0.,0.0891552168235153,0.178247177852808,
0.354877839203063,0.53106275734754,0.70762776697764,0.990252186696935,1.27356042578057,
1.51115713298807,1.74893160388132,1.98716756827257,2.22532683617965,2.55891555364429,
2.89267459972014,3.22703384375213,3.56145695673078,3.89721167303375,4.23299607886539,
4.56842361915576,4.903860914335,5.34508340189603,5.78630192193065,6.22666843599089,
6.66700708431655,7.11756063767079,7.5682067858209,8.01858915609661,8.46872836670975,
8.93454308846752,9.40018438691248,9.74654054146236,10.0921360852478,10.3150195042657,
10.5376505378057,10.7211584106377,10.9042574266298,10.9826961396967,11.0611318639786),.UNSPECIFIED.);
#647=EDGE_CURVE('E53',#567,#470,#646,.T.);
#648=ORIENTED_EDGE('',*,*,#647,.T.);
#649=ORIENTED_EDGE('',*,*,#471,.T.);
#650=ORIENTED_EDGE('',*,*,#76,.T.);
#651=EDGE_LOOP('',(#569,#648,#649,#650));
#652=FACE_BOUND('',#651,.T.);
#653=ADVANCED_FACE('F198',(#652),#561,.F.);
#654=CARTESIAN_POINT('',(-4.75000000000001,8.00000000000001,8.22724133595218));
#655=DIRECTION('',(0.,0.,-1.));
#656=DIRECTION('',(-1.,0.,0.));
#657=AXIS2_PLACEMENT_3D('',#654,#655,#656);
#658=PLANE('',#657);
#659=ORIENTED_EDGE('',*,*,#212,.F.);
#660=CARTESIAN_POINT('',(0.,7.86309421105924,8.22724133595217));
#661=CARTESIAN_POINT('',(-0.206684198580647,7.86309782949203,8.22724133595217));
#662=CARTESIAN_POINT('',(-0.413370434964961,7.86010584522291,8.22724133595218));
#663=CARTESIAN_POINT('',(-0.826620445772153,7.84753258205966,8.22724133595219));
#664=CARTESIAN_POINT('',(-1.03318416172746,7.83794924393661,8.22724133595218));
#665=CARTESIAN_POINT('',(-1.4452627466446,7.81035098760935,8.22724133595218));
#666=CARTESIAN_POINT('',(-1.65077894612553,7.79235698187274,8.22724133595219));
#667=CARTESIAN_POINT('',(-2.06041206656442,7.74477379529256,8.22724133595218));
#668=CARTESIAN_POINT('',(-2.26452989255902,7.71519301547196,8.22724133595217));
#669=CARTESIAN_POINT('',(-2.61614106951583,7.64959758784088,8.22724133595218));
#670=CARTESIAN_POINT('',(-2.76431978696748,7.61735919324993,8.22724133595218));
#671=CARTESIAN_POINT('',(-3.05799231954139,7.54125939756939,8.22724133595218));
#672=CARTESIAN_POINT('',(-3.20348124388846,7.49737869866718,8.22724133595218));
#673=CARTESIAN_POINT('',(-3.49064250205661,7.39399754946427,8.22724133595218));
#674=CARTESIAN_POINT('',(-3.63226588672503,7.3343536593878,8.22724133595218));
#675=CARTESIAN_POINT('',(-3.83687465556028,7.22993735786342,8.22724133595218));
#676=CARTESIAN_POINT('',(-3.90369987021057,7.19269224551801,8.22724133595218));
#677=CARTESIAN_POINT('',(-4.03382325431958,7.11252196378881,8.22724133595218));
#678=CARTESIAN_POINT('',(-4.09712427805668,7.0696014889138,8.22724133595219));
#679=CARTESIAN_POINT('',(-4.22060565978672,6.97609139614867,8.22724133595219));
#680=CARTESIAN_POINT('',(-4.28065351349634,6.92532429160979,8.22724133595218));
#681=CARTESIAN_POINT('',(-4.39371594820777,6.81630884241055,8.22724133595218));
#682=CARTESIAN_POINT('',(-4.44672688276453,6.75805664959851,8.22724133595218));
#683=CARTESIAN_POINT('',(-4.54354715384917,6.63298440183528,8.22724133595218));
#684=CARTESIAN_POINT('',(-4.58722851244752,6.56606321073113,8.22724133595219));
#685=CARTESIAN_POINT('',(-4.66079442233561,6.42502707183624,8.22724133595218));
#686=CARTESIAN_POINT('',(-4.69071703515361,6.35093266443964,8.22724133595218));
#687=CARTESIAN_POINT('',(-4.72740557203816,6.21937063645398,8.22724133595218));
#688=CARTESIAN_POINT('',(-4.73830722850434,6.1630479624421,8.22724133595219));
#689=CARTESIAN_POINT('',(-4.75039980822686,6.04936642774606,8.22724133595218));
#690=CARTESIAN_POINT('',(-4.75159558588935,5.9920080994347,8.22724133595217));
#691=CARTESIAN_POINT('',(-4.74417597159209,5.87796699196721,8.22724133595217));
#692=CARTESIAN_POINT('',(-4.73556478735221,5.82128393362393,8.22724133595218));
#693=CARTESIAN_POINT('',(-4.70922228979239,5.71008948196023,8.22724133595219));
#694=CARTESIAN_POINT('',(-4.69148569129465,5.65557936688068,8.22724133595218));
#695=CARTESIAN_POINT('',(-4.64219534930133,5.53554430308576,8.22724133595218));
#696=CARTESIAN_POINT('',(-4.60820278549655,5.47102431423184,8.22724133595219));
#697=CARTESIAN_POINT('',(-4.53019257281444,5.34837346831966,8.22724133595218));
#698=CARTESIAN_POINT('',(-4.48615618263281,5.29025486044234,8.22724133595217));
#699=CARTESIAN_POINT('',(-4.36826739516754,5.15495744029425,8.22724133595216));
#700=CARTESIAN_POINT('',(-4.29009919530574,5.08156629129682,8.22724133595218));
#701=CARTESIAN_POINT('',(-4.123564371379,4.9476279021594,8.22724133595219));
#702=CARTESIAN_POINT('',(-4.03517935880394,4.88710439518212,8.22724133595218));
#703=CARTESIAN_POINT('',(-3.86199693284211,4.78305623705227,8.22724133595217));
#704=CARTESIAN_POINT('',(-3.77786807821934,4.73839551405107,8.22724133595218));
#705=CARTESIAN_POINT('',(-3.60605635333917,4.65643568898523,8.22724133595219));
#706=CARTESIAN_POINT('',(-3.51837048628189,4.61914295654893,8.22724133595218));
#707=CARTESIAN_POINT('',(-3.34037999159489,4.5507381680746,8.22724133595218));
#708=CARTESIAN_POINT('',(-3.2500689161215,4.51964312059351,8.22724133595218));
#709=CARTESIAN_POINT('',(-3.06784548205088,4.4628100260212,8.22724133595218));
#710=CARTESIAN_POINT('',(-2.97593388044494,4.43706951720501,8.22724133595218));
#711=CARTESIAN_POINT('',(-2.73297019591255,4.3753681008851,8.22724133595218));
#712=CARTESIAN_POINT('',(-2.58097839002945,4.3431215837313,8.22724133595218));
#713=CARTESIAN_POINT('',(-2.27531090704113,4.28775252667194,8.22724133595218));
#714=CARTESIAN_POINT('',(-2.12163417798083,4.2646360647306,8.22724133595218));
#715=CARTESIAN_POINT('',(-1.81301597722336,4.22540230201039,8.22724133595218));
#716=CARTESIAN_POINT('',(-1.65807228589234,4.20930290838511,8.22724133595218));
#717=CARTESIAN_POINT('',(-1.34776570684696,4.18261700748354,8.22724133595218));
#718=CARTESIAN_POINT('',(-1.19240292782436,4.17202918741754,8.22724133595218));
#719=CARTESIAN_POINT('',(-0.880551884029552,4.15520395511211,8.22724133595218));
#720=CARTESIAN_POINT('',(-0.724062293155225,4.14899196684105,8.22724133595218));
#721=CARTESIAN_POINT('',(-0.410973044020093,4.14031974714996,8.22724133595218));
#722=CARTESIAN_POINT('',(-0.254373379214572,4.13785976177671,8.22724133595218));
#723=CARTESIAN_POINT('',(0.0586204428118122,4.13640652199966,8.22724133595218));
#724=CARTESIAN_POINT('',(0.215014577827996,4.13740837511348,8.22724133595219));
#725=CARTESIAN_POINT('',(0.527730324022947,4.14298683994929,8.22724133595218));
#726=CARTESIAN_POINT('',(0.684051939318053,4.14756321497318,8.22724133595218));
#727=CARTESIAN_POINT('',(1.01826864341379,4.16172647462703,8.22724133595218));
#728=CARTESIAN_POINT('',(1.19613931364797,4.17192188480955,8.22724133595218));
#729=CARTESIAN_POINT('',(1.55144210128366,4.19904799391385,8.22724133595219));
#730=CARTESIAN_POINT('',(1.72887407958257,4.21598060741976,8.22724133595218));
#731=CARTESIAN_POINT('',(2.08147469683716,4.25864363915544,8.22724133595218));
#732=CARTESIAN_POINT('',(2.2566505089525,4.28431272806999,8.22724133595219));
#733=CARTESIAN_POINT('',(2.6049445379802,4.34752349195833,8.22724133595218));
#734=CARTESIAN_POINT('',(2.77806298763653,4.38506381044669,8.22724133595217));
#735=CARTESIAN_POINT('',(3.06972079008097,4.46282421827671,8.22724133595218));
#736=CARTESIAN_POINT('',(3.18932341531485,4.4990015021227,8.22724133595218));
#737=CARTESIAN_POINT('',(3.42499098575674,4.58131258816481,8.22724133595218));
#738=CARTESIAN_POINT('',(3.54105975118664,4.62743516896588,8.22724133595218));
#739=CARTESIAN_POINT('',(3.76871321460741,4.73258074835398,8.22724133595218));
#740=CARTESIAN_POINT('',(3.88024208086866,4.79172705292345,8.22724133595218));
#741=CARTESIAN_POINT('',(4.09352743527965,4.92559645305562,8.22724133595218));
#742=CARTESIAN_POINT('',(4.19531194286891,5.00027280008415,8.22724133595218));
#743=CARTESIAN_POINT('',(4.34424622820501,5.1339564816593,8.22724133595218));
#744=CARTESIAN_POINT('',(4.39676160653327,5.18695469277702,8.22724133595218));
#745=CARTESIAN_POINT('',(4.49386382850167,5.29991260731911,8.22724133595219));
#746=CARTESIAN_POINT('',(4.5384499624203,5.35987293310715,8.22724133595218));
#747=CARTESIAN_POINT('',(4.61742896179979,5.48738312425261,8.22724133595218));
#748=CARTESIAN_POINT('',(4.65168292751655,5.55502090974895,8.22724133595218));
#749=CARTESIAN_POINT('',(4.70594056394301,5.69579105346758,8.22724133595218));
#750=CARTESIAN_POINT('',(4.72597405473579,5.76891155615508,8.22724133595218));
#751=CARTESIAN_POINT('',(4.74770863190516,5.90689178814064,8.22724133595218));
#752=CARTESIAN_POINT('',(4.75166049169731,5.97139761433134,8.22724133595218));
#753=CARTESIAN_POINT('',(4.74706633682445,6.09996082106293,8.22724133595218));
#754=CARTESIAN_POINT('',(4.73852202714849,6.16401826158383,8.22724133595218));
#755=CARTESIAN_POINT('',(4.71150906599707,6.28197730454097,8.22724133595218));
#756=CARTESIAN_POINT('',(4.69433239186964,6.33618455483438,8.22724133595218));
#757=CARTESIAN_POINT('',(4.65211479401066,6.44140800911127,8.22724133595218));
#758=CARTESIAN_POINT('',(4.62707206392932,6.49242347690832,8.22724133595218));
#759=CARTESIAN_POINT('',(4.55726563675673,6.61350833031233,8.22724133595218));
#760=CARTESIAN_POINT('',(4.50874614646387,6.68141021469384,8.22724133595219));
#761=CARTESIAN_POINT('',(4.40153522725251,6.80863302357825,8.22724133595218));
#762=CARTESIAN_POINT('',(4.34281937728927,6.86793270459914,8.22724133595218));
#763=CARTESIAN_POINT('',(4.18223991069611,7.01038551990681,8.22724133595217));
#764=CARTESIAN_POINT('',(4.075061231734,7.08749984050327,8.22724133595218));
#765=CARTESIAN_POINT('',(3.85058975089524,7.22500735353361,8.22724133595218));
#766=CARTESIAN_POINT('',(3.73327357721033,7.28536047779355,8.22724133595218));
#767=CARTESIAN_POINT('',(3.49483121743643,7.39172183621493,8.22724133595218));
#768=CARTESIAN_POINT('',(3.37380422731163,7.4379573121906,8.22724133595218));
#769=CARTESIAN_POINT('',(3.12824195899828,7.52010489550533,8.22724133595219));
#770=CARTESIAN_POINT('',(3.00370313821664,7.5560061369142,8.22724133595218));
#771=CARTESIAN_POINT('',(2.75236111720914,7.6195738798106,8.22724133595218));
#772=CARTESIAN_POINT('',(2.62555444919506,7.64722637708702,8.22724133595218));
#773=CARTESIAN_POINT('',(2.37065949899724,7.69587702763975,8.22724133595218));
#774=CARTESIAN_POINT('',(2.24257083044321,7.71687310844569,8.22724133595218));
#775=CARTESIAN_POINT('',(1.93925651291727,7.76014569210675,8.22724133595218));
#776=CARTESIAN_POINT('',(1.76371117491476,7.78014693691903,8.22724133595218));
#777=CARTESIAN_POINT('',(1.4119267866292,7.81276338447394,8.22724133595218));
#778=CARTESIAN_POINT('',(1.2356875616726,7.8253765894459,8.22724133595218));
#779=CARTESIAN_POINT('',(0.882918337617,7.84489642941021,8.22724133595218));
#780=CARTESIAN_POINT('',(0.706388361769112,7.85180350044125,8.22724133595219));
#781=CARTESIAN_POINT('',(0.353239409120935,7.86090050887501,8.22724133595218));
#782=CARTESIAN_POINT('',(0.176620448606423,7.86309111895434,8.22724133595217));
#783=CARTESIAN_POINT('',(0.,7.86309421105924,8.22724133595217));
#784=B_SPLINE_CURVE_WITH_KNOTS('',3,(#660,#661,#662,#663,#664,#665,#666,#667,#668,#669,#670,
#671,#672,#673,#674,#675,#676,#677,#678,#679,#680,#681,#682,#683,#684,#685,#686,#687,#688,#689,
#690,#691,#692,#693,#694,#695,#696,#697,#698,#699,#700,#701,#702,#703,#704,#705,#706,#707,#708,
#709,#710,#711,#712,#713,#714,#715,#716,#717,#718,#719,#720,#721,#722,#723,#724,#725,#726,#727,
#728,#729,#730,#731,#732,#733,#734,#735,#736,#737,#738,#739,#740,#741,#742,#743,#744,#745,#746,
#747,#748,#749,#750,#751,#752,#753,#754,#755,#756,#757,#758,#759,#760,#761,#762,#763,#764,#765,
#766,#767,#768,#769,#770,#771,#772,#773,#774,#775,#776,#777,#778,#779,#780,#781,#782,#783),
.UNSPECIFIED.,.T.,.F.,(4,2,2,2,2,2,2,2,2,2,2,2,2,2,2,2,2,2,2,2,2,2,2,2,2,2,2,2,2,2,2,2,2,2,2,2,
2,2,2,2,2,2,2,2,2,2,2,2,2,2,2,2,2,2,2,2,2,2,2,2,2,4),(0.,0.620032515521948,1.24025882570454,
1.85895112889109,2.47719567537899,2.9317741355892,3.38711084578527,3.84674284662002,
4.0760251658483,4.30511900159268,4.5404717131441,4.77594590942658,5.01446787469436,
5.25232597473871,5.42366572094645,5.59491976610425,5.76610036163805,5.93738021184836,
6.15495372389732,6.37293658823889,6.69280248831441,7.01325332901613,7.29858144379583,
7.58415515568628,7.87050210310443,8.15671711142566,8.6224309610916,9.08845432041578,
9.55566007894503,10.022754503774,10.4925408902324,10.9623580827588,11.4315115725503,
11.9006339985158,12.4350252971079,12.9695685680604,13.5004342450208,14.0312392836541,
14.4057708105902,14.7798819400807,15.1577002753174,15.5343973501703,15.7576422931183,
15.9809072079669,16.2070519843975,16.4327211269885,16.6254194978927,16.8180915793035,
16.9879971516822,17.1579417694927,17.4068911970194,17.6564453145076,18.0503256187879,
18.4451395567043,18.8332152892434,19.2216975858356,19.6108357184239,20.0000948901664,
20.5299119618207,21.0598722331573,21.589792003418,22.1196361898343),.UNSPECIFIED.);
#785=EDGE_CURVE('E11',#205,#567,#784,.T.);
#786=ORIENTED_EDGE('',*,*,#785,.T.);
#787=ORIENTED_EDGE('',*,*,#568,.T.);
#788=ORIENTED_EDGE('',*,*,#68,.T.);
#789=EDGE_LOOP('',(#659,#786,#787,#788));
#790=FACE_BOUND('',#789,.T.);
#791=ADVANCED_FACE('F195',(#790),#658,.F.);
#792=CARTESIAN_POINT('',(0.,8.00000000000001,0.));
#793=DIRECTION('',(0.,-1.,0.));
#794=DIRECTION('',(0.,0.,-1.));
#795=AXIS2_PLACEMENT_3D('',#792,#793,#794);
#796=CYLINDRICAL_SURFACE('',#795,5.);
#797=ORIENTED_EDGE('',*,*,#42,.T.);
#798=EDGE_LOOP('',(#797));
#799=FACE_BOUND('',#798,.T.);
#800=ORIENTED_EDGE('',*,*,#109,.F.);
#801=EDGE_LOOP('',(#800));
#802=FACE_BOUND('',#801,.T.);
#803=ADVANCED_FACE('F151',(#799,#802),#796,.F.);
#804=CARTESIAN_POINT('',(0.,6.00000000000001,0.));
#805=DIRECTION('',(0.,-1.,0.));
#806=DIRECTION('',(0.,0.,-1.));
#807=AXIS2_PLACEMENT_3D('',#804,#805,#806);
#808=TOROIDAL_SURFACE('',#807,7.49999999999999,2.);
#809=ORIENTED_EDGE('',*,*,#31,.T.);
#810=EDGE_LOOP('',(#809));
#811=FACE_BOUND('',#810,.T.);
#812=ORIENTED_EDGE('',*,*,#308,.F.);
#813=ORIENTED_EDGE('',*,*,#453,.F.);
#814=ORIENTED_EDGE('',*,*,#550,.F.);
#815=ORIENTED_EDGE('',*,*,#647,.F.);
#816=ORIENTED_EDGE('',*,*,#785,.F.);
#817=ORIENTED_EDGE('',*,*,#206,.F.);
#818=EDGE_LOOP('',(#812,#813,#814,#815,#816,#817));
#819=FACE_BOUND('',#818,.T.);
#820=ADVANCED_FACE('F92',(#811,#819),#808,.T.);
#821=CLOSED_SHELL('',(#46,#113,#217,#314,#459,#556,#653,#791,#803,#820));
#822=MANIFOLD_SOLID_BREP('B2',#821);
#823=ADVANCED_BREP_SHAPE_REPRESENTATION('',(#18,#822),#14);
#824=SHAPE_DEFINITION_REPRESENTATION(#9,#823);
ENDSEC;
END-ISO-10303-21;
